VERSION 5.7 ;
BUSBITCHARS "[]" ;
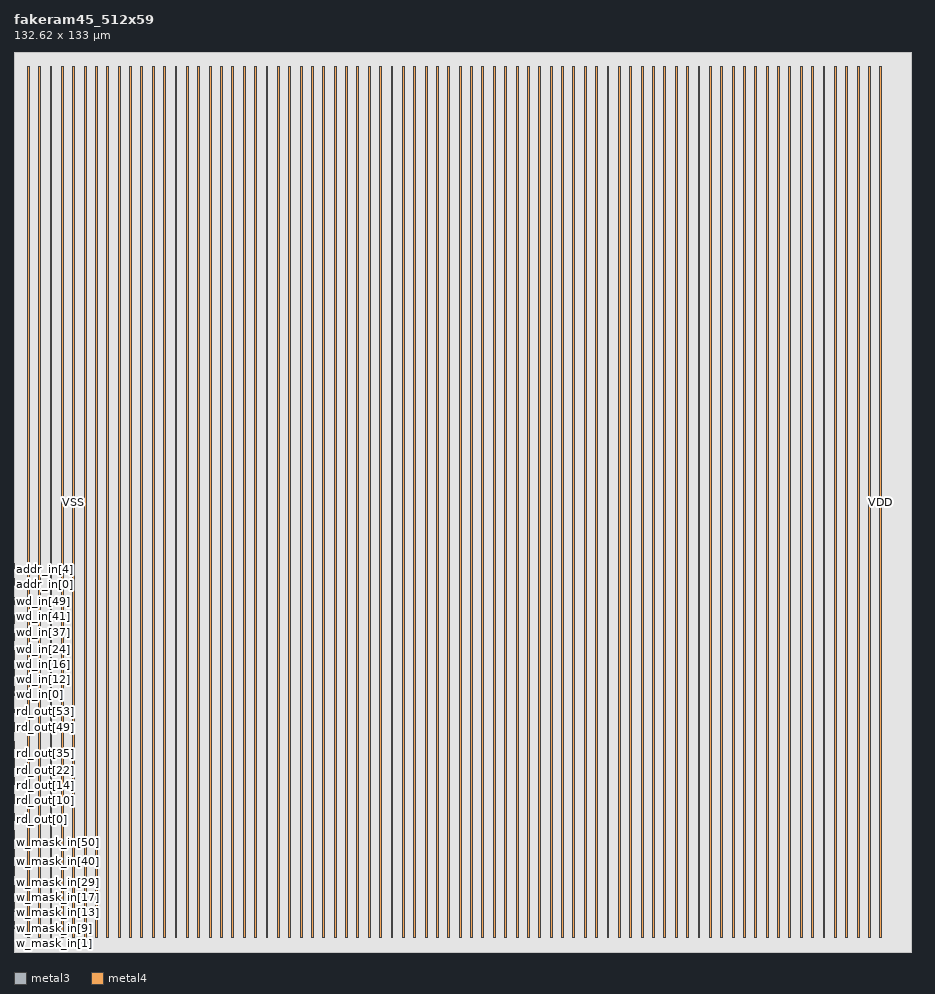
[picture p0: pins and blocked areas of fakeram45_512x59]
MACRO fakeram45_512x59
  FOREIGN fakeram45_512x59 0 0 ;
  SYMMETRY X Y R90 ;
  SIZE 132.620 BY 133.000 ;
  CLASS BLOCK ;
  PIN w_mask_in[0]
    DIRECTION INPUT ;
    USE SIGNAL ;
    SHAPE ABUTMENT ;
    PORT
      LAYER metal3 ;
      RECT 0.000 2.135 0.070 2.205 ;
    END
  END w_mask_in[0]
  PIN w_mask_in[1]
    DIRECTION INPUT ;
    USE SIGNAL ;
    SHAPE ABUTMENT ;
    PORT
      LAYER metal3 ;
      RECT 0.000 2.415 0.070 2.485 ;
    END
  END w_mask_in[1]
  PIN w_mask_in[2]
    DIRECTION INPUT ;
    USE SIGNAL ;
    SHAPE ABUTMENT ;
    PORT
      LAYER metal3 ;
      RECT 0.000 2.695 0.070 2.765 ;
    END
  END w_mask_in[2]
  PIN w_mask_in[3]
    DIRECTION INPUT ;
    USE SIGNAL ;
    SHAPE ABUTMENT ;
    PORT
      LAYER metal3 ;
      RECT 0.000 2.975 0.070 3.045 ;
    END
  END w_mask_in[3]
  PIN w_mask_in[4]
    DIRECTION INPUT ;
    USE SIGNAL ;
    SHAPE ABUTMENT ;
    PORT
      LAYER metal3 ;
      RECT 0.000 3.255 0.070 3.325 ;
    END
  END w_mask_in[4]
  PIN w_mask_in[5]
    DIRECTION INPUT ;
    USE SIGNAL ;
    SHAPE ABUTMENT ;
    PORT
      LAYER metal3 ;
      RECT 0.000 3.535 0.070 3.605 ;
    END
  END w_mask_in[5]
  PIN w_mask_in[6]
    DIRECTION INPUT ;
    USE SIGNAL ;
    SHAPE ABUTMENT ;
    PORT
      LAYER metal3 ;
      RECT 0.000 3.815 0.070 3.885 ;
    END
  END w_mask_in[6]
  PIN w_mask_in[7]
    DIRECTION INPUT ;
    USE SIGNAL ;
    SHAPE ABUTMENT ;
    PORT
      LAYER metal3 ;
      RECT 0.000 4.095 0.070 4.165 ;
    END
  END w_mask_in[7]
  PIN w_mask_in[8]
    DIRECTION INPUT ;
    USE SIGNAL ;
    SHAPE ABUTMENT ;
    PORT
      LAYER metal3 ;
      RECT 0.000 4.375 0.070 4.445 ;
    END
  END w_mask_in[8]
  PIN w_mask_in[9]
    DIRECTION INPUT ;
    USE SIGNAL ;
    SHAPE ABUTMENT ;
    PORT
      LAYER metal3 ;
      RECT 0.000 4.655 0.070 4.725 ;
    END
  END w_mask_in[9]
  PIN w_mask_in[10]
    DIRECTION INPUT ;
    USE SIGNAL ;
    SHAPE ABUTMENT ;
    PORT
      LAYER metal3 ;
      RECT 0.000 4.935 0.070 5.005 ;
    END
  END w_mask_in[10]
  PIN w_mask_in[11]
    DIRECTION INPUT ;
    USE SIGNAL ;
    SHAPE ABUTMENT ;
    PORT
      LAYER metal3 ;
      RECT 0.000 5.215 0.070 5.285 ;
    END
  END w_mask_in[11]
  PIN w_mask_in[12]
    DIRECTION INPUT ;
    USE SIGNAL ;
    SHAPE ABUTMENT ;
    PORT
      LAYER metal3 ;
      RECT 0.000 5.495 0.070 5.565 ;
    END
  END w_mask_in[12]
  PIN w_mask_in[13]
    DIRECTION INPUT ;
    USE SIGNAL ;
    SHAPE ABUTMENT ;
    PORT
      LAYER metal3 ;
      RECT 0.000 5.775 0.070 5.845 ;
    END
  END w_mask_in[13]
  PIN w_mask_in[14]
    DIRECTION INPUT ;
    USE SIGNAL ;
    SHAPE ABUTMENT ;
    PORT
      LAYER metal3 ;
      RECT 0.000 6.055 0.070 6.125 ;
    END
  END w_mask_in[14]
  PIN w_mask_in[15]
    DIRECTION INPUT ;
    USE SIGNAL ;
    SHAPE ABUTMENT ;
    PORT
      LAYER metal3 ;
      RECT 0.000 6.335 0.070 6.405 ;
    END
  END w_mask_in[15]
  PIN w_mask_in[16]
    DIRECTION INPUT ;
    USE SIGNAL ;
    SHAPE ABUTMENT ;
    PORT
      LAYER metal3 ;
      RECT 0.000 6.615 0.070 6.685 ;
    END
  END w_mask_in[16]
  PIN w_mask_in[17]
    DIRECTION INPUT ;
    USE SIGNAL ;
    SHAPE ABUTMENT ;
    PORT
      LAYER metal3 ;
      RECT 0.000 6.895 0.070 6.965 ;
    END
  END w_mask_in[17]
  PIN w_mask_in[18]
    DIRECTION INPUT ;
    USE SIGNAL ;
    SHAPE ABUTMENT ;
    PORT
      LAYER metal3 ;
      RECT 0.000 7.175 0.070 7.245 ;
    END
  END w_mask_in[18]
  PIN w_mask_in[19]
    DIRECTION INPUT ;
    USE SIGNAL ;
    SHAPE ABUTMENT ;
    PORT
      LAYER metal3 ;
      RECT 0.000 7.455 0.070 7.525 ;
    END
  END w_mask_in[19]
  PIN w_mask_in[20]
    DIRECTION INPUT ;
    USE SIGNAL ;
    SHAPE ABUTMENT ;
    PORT
      LAYER metal3 ;
      RECT 0.000 7.735 0.070 7.805 ;
    END
  END w_mask_in[20]
  PIN w_mask_in[21]
    DIRECTION INPUT ;
    USE SIGNAL ;
    SHAPE ABUTMENT ;
    PORT
      LAYER metal3 ;
      RECT 0.000 8.015 0.070 8.085 ;
    END
  END w_mask_in[21]
  PIN w_mask_in[22]
    DIRECTION INPUT ;
    USE SIGNAL ;
    SHAPE ABUTMENT ;
    PORT
      LAYER metal3 ;
      RECT 0.000 8.295 0.070 8.365 ;
    END
  END w_mask_in[22]
  PIN w_mask_in[23]
    DIRECTION INPUT ;
    USE SIGNAL ;
    SHAPE ABUTMENT ;
    PORT
      LAYER metal3 ;
      RECT 0.000 8.575 0.070 8.645 ;
    END
  END w_mask_in[23]
  PIN w_mask_in[24]
    DIRECTION INPUT ;
    USE SIGNAL ;
    SHAPE ABUTMENT ;
    PORT
      LAYER metal3 ;
      RECT 0.000 8.855 0.070 8.925 ;
    END
  END w_mask_in[24]
  PIN w_mask_in[25]
    DIRECTION INPUT ;
    USE SIGNAL ;
    SHAPE ABUTMENT ;
    PORT
      LAYER metal3 ;
      RECT 0.000 9.135 0.070 9.205 ;
    END
  END w_mask_in[25]
  PIN w_mask_in[26]
    DIRECTION INPUT ;
    USE SIGNAL ;
    SHAPE ABUTMENT ;
    PORT
      LAYER metal3 ;
      RECT 0.000 9.415 0.070 9.485 ;
    END
  END w_mask_in[26]
  PIN w_mask_in[27]
    DIRECTION INPUT ;
    USE SIGNAL ;
    SHAPE ABUTMENT ;
    PORT
      LAYER metal3 ;
      RECT 0.000 9.695 0.070 9.765 ;
    END
  END w_mask_in[27]
  PIN w_mask_in[28]
    DIRECTION INPUT ;
    USE SIGNAL ;
    SHAPE ABUTMENT ;
    PORT
      LAYER metal3 ;
      RECT 0.000 9.975 0.070 10.045 ;
    END
  END w_mask_in[28]
  PIN w_mask_in[29]
    DIRECTION INPUT ;
    USE SIGNAL ;
    SHAPE ABUTMENT ;
    PORT
      LAYER metal3 ;
      RECT 0.000 10.255 0.070 10.325 ;
    END
  END w_mask_in[29]
  PIN w_mask_in[30]
    DIRECTION INPUT ;
    USE SIGNAL ;
    SHAPE ABUTMENT ;
    PORT
      LAYER metal3 ;
      RECT 0.000 10.535 0.070 10.605 ;
    END
  END w_mask_in[30]
  PIN w_mask_in[31]
    DIRECTION INPUT ;
    USE SIGNAL ;
    SHAPE ABUTMENT ;
    PORT
      LAYER metal3 ;
      RECT 0.000 10.815 0.070 10.885 ;
    END
  END w_mask_in[31]
  PIN w_mask_in[32]
    DIRECTION INPUT ;
    USE SIGNAL ;
    SHAPE ABUTMENT ;
    PORT
      LAYER metal3 ;
      RECT 0.000 11.095 0.070 11.165 ;
    END
  END w_mask_in[32]
  PIN w_mask_in[33]
    DIRECTION INPUT ;
    USE SIGNAL ;
    SHAPE ABUTMENT ;
    PORT
      LAYER metal3 ;
      RECT 0.000 11.375 0.070 11.445 ;
    END
  END w_mask_in[33]
  PIN w_mask_in[34]
    DIRECTION INPUT ;
    USE SIGNAL ;
    SHAPE ABUTMENT ;
    PORT
      LAYER metal3 ;
      RECT 0.000 11.655 0.070 11.725 ;
    END
  END w_mask_in[34]
  PIN w_mask_in[35]
    DIRECTION INPUT ;
    USE SIGNAL ;
    SHAPE ABUTMENT ;
    PORT
      LAYER metal3 ;
      RECT 0.000 11.935 0.070 12.005 ;
    END
  END w_mask_in[35]
  PIN w_mask_in[36]
    DIRECTION INPUT ;
    USE SIGNAL ;
    SHAPE ABUTMENT ;
    PORT
      LAYER metal3 ;
      RECT 0.000 12.215 0.070 12.285 ;
    END
  END w_mask_in[36]
  PIN w_mask_in[37]
    DIRECTION INPUT ;
    USE SIGNAL ;
    SHAPE ABUTMENT ;
    PORT
      LAYER metal3 ;
      RECT 0.000 12.495 0.070 12.565 ;
    END
  END w_mask_in[37]
  PIN w_mask_in[38]
    DIRECTION INPUT ;
    USE SIGNAL ;
    SHAPE ABUTMENT ;
    PORT
      LAYER metal3 ;
      RECT 0.000 12.775 0.070 12.845 ;
    END
  END w_mask_in[38]
  PIN w_mask_in[39]
    DIRECTION INPUT ;
    USE SIGNAL ;
    SHAPE ABUTMENT ;
    PORT
      LAYER metal3 ;
      RECT 0.000 13.055 0.070 13.125 ;
    END
  END w_mask_in[39]
  PIN w_mask_in[40]
    DIRECTION INPUT ;
    USE SIGNAL ;
    SHAPE ABUTMENT ;
    PORT
      LAYER metal3 ;
      RECT 0.000 13.335 0.070 13.405 ;
    END
  END w_mask_in[40]
  PIN w_mask_in[41]
    DIRECTION INPUT ;
    USE SIGNAL ;
    SHAPE ABUTMENT ;
    PORT
      LAYER metal3 ;
      RECT 0.000 13.615 0.070 13.685 ;
    END
  END w_mask_in[41]
  PIN w_mask_in[42]
    DIRECTION INPUT ;
    USE SIGNAL ;
    SHAPE ABUTMENT ;
    PORT
      LAYER metal3 ;
      RECT 0.000 13.895 0.070 13.965 ;
    END
  END w_mask_in[42]
  PIN w_mask_in[43]
    DIRECTION INPUT ;
    USE SIGNAL ;
    SHAPE ABUTMENT ;
    PORT
      LAYER metal3 ;
      RECT 0.000 14.175 0.070 14.245 ;
    END
  END w_mask_in[43]
  PIN w_mask_in[44]
    DIRECTION INPUT ;
    USE SIGNAL ;
    SHAPE ABUTMENT ;
    PORT
      LAYER metal3 ;
      RECT 0.000 14.455 0.070 14.525 ;
    END
  END w_mask_in[44]
  PIN w_mask_in[45]
    DIRECTION INPUT ;
    USE SIGNAL ;
    SHAPE ABUTMENT ;
    PORT
      LAYER metal3 ;
      RECT 0.000 14.735 0.070 14.805 ;
    END
  END w_mask_in[45]
  PIN w_mask_in[46]
    DIRECTION INPUT ;
    USE SIGNAL ;
    SHAPE ABUTMENT ;
    PORT
      LAYER metal3 ;
      RECT 0.000 15.015 0.070 15.085 ;
    END
  END w_mask_in[46]
  PIN w_mask_in[47]
    DIRECTION INPUT ;
    USE SIGNAL ;
    SHAPE ABUTMENT ;
    PORT
      LAYER metal3 ;
      RECT 0.000 15.295 0.070 15.365 ;
    END
  END w_mask_in[47]
  PIN w_mask_in[48]
    DIRECTION INPUT ;
    USE SIGNAL ;
    SHAPE ABUTMENT ;
    PORT
      LAYER metal3 ;
      RECT 0.000 15.575 0.070 15.645 ;
    END
  END w_mask_in[48]
  PIN w_mask_in[49]
    DIRECTION INPUT ;
    USE SIGNAL ;
    SHAPE ABUTMENT ;
    PORT
      LAYER metal3 ;
      RECT 0.000 15.855 0.070 15.925 ;
    END
  END w_mask_in[49]
  PIN w_mask_in[50]
    DIRECTION INPUT ;
    USE SIGNAL ;
    SHAPE ABUTMENT ;
    PORT
      LAYER metal3 ;
      RECT 0.000 16.135 0.070 16.205 ;
    END
  END w_mask_in[50]
  PIN w_mask_in[51]
    DIRECTION INPUT ;
    USE SIGNAL ;
    SHAPE ABUTMENT ;
    PORT
      LAYER metal3 ;
      RECT 0.000 16.415 0.070 16.485 ;
    END
  END w_mask_in[51]
  PIN w_mask_in[52]
    DIRECTION INPUT ;
    USE SIGNAL ;
    SHAPE ABUTMENT ;
    PORT
      LAYER metal3 ;
      RECT 0.000 16.695 0.070 16.765 ;
    END
  END w_mask_in[52]
  PIN w_mask_in[53]
    DIRECTION INPUT ;
    USE SIGNAL ;
    SHAPE ABUTMENT ;
    PORT
      LAYER metal3 ;
      RECT 0.000 16.975 0.070 17.045 ;
    END
  END w_mask_in[53]
  PIN w_mask_in[54]
    DIRECTION INPUT ;
    USE SIGNAL ;
    SHAPE ABUTMENT ;
    PORT
      LAYER metal3 ;
      RECT 0.000 17.255 0.070 17.325 ;
    END
  END w_mask_in[54]
  PIN w_mask_in[55]
    DIRECTION INPUT ;
    USE SIGNAL ;
    SHAPE ABUTMENT ;
    PORT
      LAYER metal3 ;
      RECT 0.000 17.535 0.070 17.605 ;
    END
  END w_mask_in[55]
  PIN w_mask_in[56]
    DIRECTION INPUT ;
    USE SIGNAL ;
    SHAPE ABUTMENT ;
    PORT
      LAYER metal3 ;
      RECT 0.000 17.815 0.070 17.885 ;
    END
  END w_mask_in[56]
  PIN w_mask_in[57]
    DIRECTION INPUT ;
    USE SIGNAL ;
    SHAPE ABUTMENT ;
    PORT
      LAYER metal3 ;
      RECT 0.000 18.095 0.070 18.165 ;
    END
  END w_mask_in[57]
  PIN w_mask_in[58]
    DIRECTION INPUT ;
    USE SIGNAL ;
    SHAPE ABUTMENT ;
    PORT
      LAYER metal3 ;
      RECT 0.000 18.375 0.070 18.445 ;
    END
  END w_mask_in[58]
  PIN rd_out[0]
    DIRECTION OUTPUT ;
    USE SIGNAL ;
    SHAPE ABUTMENT ;
    PORT
      LAYER metal3 ;
      RECT 0.000 19.495 0.070 19.565 ;
    END
  END rd_out[0]
  PIN rd_out[1]
    DIRECTION OUTPUT ;
    USE SIGNAL ;
    SHAPE ABUTMENT ;
    PORT
      LAYER metal3 ;
      RECT 0.000 19.775 0.070 19.845 ;
    END
  END rd_out[1]
  PIN rd_out[2]
    DIRECTION OUTPUT ;
    USE SIGNAL ;
    SHAPE ABUTMENT ;
    PORT
      LAYER metal3 ;
      RECT 0.000 20.055 0.070 20.125 ;
    END
  END rd_out[2]
  PIN rd_out[3]
    DIRECTION OUTPUT ;
    USE SIGNAL ;
    SHAPE ABUTMENT ;
    PORT
      LAYER metal3 ;
      RECT 0.000 20.335 0.070 20.405 ;
    END
  END rd_out[3]
  PIN rd_out[4]
    DIRECTION OUTPUT ;
    USE SIGNAL ;
    SHAPE ABUTMENT ;
    PORT
      LAYER metal3 ;
      RECT 0.000 20.615 0.070 20.685 ;
    END
  END rd_out[4]
  PIN rd_out[5]
    DIRECTION OUTPUT ;
    USE SIGNAL ;
    SHAPE ABUTMENT ;
    PORT
      LAYER metal3 ;
      RECT 0.000 20.895 0.070 20.965 ;
    END
  END rd_out[5]
  PIN rd_out[6]
    DIRECTION OUTPUT ;
    USE SIGNAL ;
    SHAPE ABUTMENT ;
    PORT
      LAYER metal3 ;
      RECT 0.000 21.175 0.070 21.245 ;
    END
  END rd_out[6]
  PIN rd_out[7]
    DIRECTION OUTPUT ;
    USE SIGNAL ;
    SHAPE ABUTMENT ;
    PORT
      LAYER metal3 ;
      RECT 0.000 21.455 0.070 21.525 ;
    END
  END rd_out[7]
  PIN rd_out[8]
    DIRECTION OUTPUT ;
    USE SIGNAL ;
    SHAPE ABUTMENT ;
    PORT
      LAYER metal3 ;
      RECT 0.000 21.735 0.070 21.805 ;
    END
  END rd_out[8]
  PIN rd_out[9]
    DIRECTION OUTPUT ;
    USE SIGNAL ;
    SHAPE ABUTMENT ;
    PORT
      LAYER metal3 ;
      RECT 0.000 22.015 0.070 22.085 ;
    END
  END rd_out[9]
  PIN rd_out[10]
    DIRECTION OUTPUT ;
    USE SIGNAL ;
    SHAPE ABUTMENT ;
    PORT
      LAYER metal3 ;
      RECT 0.000 22.295 0.070 22.365 ;
    END
  END rd_out[10]
  PIN rd_out[11]
    DIRECTION OUTPUT ;
    USE SIGNAL ;
    SHAPE ABUTMENT ;
    PORT
      LAYER metal3 ;
      RECT 0.000 22.575 0.070 22.645 ;
    END
  END rd_out[11]
  PIN rd_out[12]
    DIRECTION OUTPUT ;
    USE SIGNAL ;
    SHAPE ABUTMENT ;
    PORT
      LAYER metal3 ;
      RECT 0.000 22.855 0.070 22.925 ;
    END
  END rd_out[12]
  PIN rd_out[13]
    DIRECTION OUTPUT ;
    USE SIGNAL ;
    SHAPE ABUTMENT ;
    PORT
      LAYER metal3 ;
      RECT 0.000 23.135 0.070 23.205 ;
    END
  END rd_out[13]
  PIN rd_out[14]
    DIRECTION OUTPUT ;
    USE SIGNAL ;
    SHAPE ABUTMENT ;
    PORT
      LAYER metal3 ;
      RECT 0.000 23.415 0.070 23.485 ;
    END
  END rd_out[14]
  PIN rd_out[15]
    DIRECTION OUTPUT ;
    USE SIGNAL ;
    SHAPE ABUTMENT ;
    PORT
      LAYER metal3 ;
      RECT 0.000 23.695 0.070 23.765 ;
    END
  END rd_out[15]
  PIN rd_out[16]
    DIRECTION OUTPUT ;
    USE SIGNAL ;
    SHAPE ABUTMENT ;
    PORT
      LAYER metal3 ;
      RECT 0.000 23.975 0.070 24.045 ;
    END
  END rd_out[16]
  PIN rd_out[17]
    DIRECTION OUTPUT ;
    USE SIGNAL ;
    SHAPE ABUTMENT ;
    PORT
      LAYER metal3 ;
      RECT 0.000 24.255 0.070 24.325 ;
    END
  END rd_out[17]
  PIN rd_out[18]
    DIRECTION OUTPUT ;
    USE SIGNAL ;
    SHAPE ABUTMENT ;
    PORT
      LAYER metal3 ;
      RECT 0.000 24.535 0.070 24.605 ;
    END
  END rd_out[18]
  PIN rd_out[19]
    DIRECTION OUTPUT ;
    USE SIGNAL ;
    SHAPE ABUTMENT ;
    PORT
      LAYER metal3 ;
      RECT 0.000 24.815 0.070 24.885 ;
    END
  END rd_out[19]
  PIN rd_out[20]
    DIRECTION OUTPUT ;
    USE SIGNAL ;
    SHAPE ABUTMENT ;
    PORT
      LAYER metal3 ;
      RECT 0.000 25.095 0.070 25.165 ;
    END
  END rd_out[20]
  PIN rd_out[21]
    DIRECTION OUTPUT ;
    USE SIGNAL ;
    SHAPE ABUTMENT ;
    PORT
      LAYER metal3 ;
      RECT 0.000 25.375 0.070 25.445 ;
    END
  END rd_out[21]
  PIN rd_out[22]
    DIRECTION OUTPUT ;
    USE SIGNAL ;
    SHAPE ABUTMENT ;
    PORT
      LAYER metal3 ;
      RECT 0.000 25.655 0.070 25.725 ;
    END
  END rd_out[22]
  PIN rd_out[23]
    DIRECTION OUTPUT ;
    USE SIGNAL ;
    SHAPE ABUTMENT ;
    PORT
      LAYER metal3 ;
      RECT 0.000 25.935 0.070 26.005 ;
    END
  END rd_out[23]
  PIN rd_out[24]
    DIRECTION OUTPUT ;
    USE SIGNAL ;
    SHAPE ABUTMENT ;
    PORT
      LAYER metal3 ;
      RECT 0.000 26.215 0.070 26.285 ;
    END
  END rd_out[24]
  PIN rd_out[25]
    DIRECTION OUTPUT ;
    USE SIGNAL ;
    SHAPE ABUTMENT ;
    PORT
      LAYER metal3 ;
      RECT 0.000 26.495 0.070 26.565 ;
    END
  END rd_out[25]
  PIN rd_out[26]
    DIRECTION OUTPUT ;
    USE SIGNAL ;
    SHAPE ABUTMENT ;
    PORT
      LAYER metal3 ;
      RECT 0.000 26.775 0.070 26.845 ;
    END
  END rd_out[26]
  PIN rd_out[27]
    DIRECTION OUTPUT ;
    USE SIGNAL ;
    SHAPE ABUTMENT ;
    PORT
      LAYER metal3 ;
      RECT 0.000 27.055 0.070 27.125 ;
    END
  END rd_out[27]
  PIN rd_out[28]
    DIRECTION OUTPUT ;
    USE SIGNAL ;
    SHAPE ABUTMENT ;
    PORT
      LAYER metal3 ;
      RECT 0.000 27.335 0.070 27.405 ;
    END
  END rd_out[28]
  PIN rd_out[29]
    DIRECTION OUTPUT ;
    USE SIGNAL ;
    SHAPE ABUTMENT ;
    PORT
      LAYER metal3 ;
      RECT 0.000 27.615 0.070 27.685 ;
    END
  END rd_out[29]
  PIN rd_out[30]
    DIRECTION OUTPUT ;
    USE SIGNAL ;
    SHAPE ABUTMENT ;
    PORT
      LAYER metal3 ;
      RECT 0.000 27.895 0.070 27.965 ;
    END
  END rd_out[30]
  PIN rd_out[31]
    DIRECTION OUTPUT ;
    USE SIGNAL ;
    SHAPE ABUTMENT ;
    PORT
      LAYER metal3 ;
      RECT 0.000 28.175 0.070 28.245 ;
    END
  END rd_out[31]
  PIN rd_out[32]
    DIRECTION OUTPUT ;
    USE SIGNAL ;
    SHAPE ABUTMENT ;
    PORT
      LAYER metal3 ;
      RECT 0.000 28.455 0.070 28.525 ;
    END
  END rd_out[32]
  PIN rd_out[33]
    DIRECTION OUTPUT ;
    USE SIGNAL ;
    SHAPE ABUTMENT ;
    PORT
      LAYER metal3 ;
      RECT 0.000 28.735 0.070 28.805 ;
    END
  END rd_out[33]
  PIN rd_out[34]
    DIRECTION OUTPUT ;
    USE SIGNAL ;
    SHAPE ABUTMENT ;
    PORT
      LAYER metal3 ;
      RECT 0.000 29.015 0.070 29.085 ;
    END
  END rd_out[34]
  PIN rd_out[35]
    DIRECTION OUTPUT ;
    USE SIGNAL ;
    SHAPE ABUTMENT ;
    PORT
      LAYER metal3 ;
      RECT 0.000 29.295 0.070 29.365 ;
    END
  END rd_out[35]
  PIN rd_out[36]
    DIRECTION OUTPUT ;
    USE SIGNAL ;
    SHAPE ABUTMENT ;
    PORT
      LAYER metal3 ;
      RECT 0.000 29.575 0.070 29.645 ;
    END
  END rd_out[36]
  PIN rd_out[37]
    DIRECTION OUTPUT ;
    USE SIGNAL ;
    SHAPE ABUTMENT ;
    PORT
      LAYER metal3 ;
      RECT 0.000 29.855 0.070 29.925 ;
    END
  END rd_out[37]
  PIN rd_out[38]
    DIRECTION OUTPUT ;
    USE SIGNAL ;
    SHAPE ABUTMENT ;
    PORT
      LAYER metal3 ;
      RECT 0.000 30.135 0.070 30.205 ;
    END
  END rd_out[38]
  PIN rd_out[39]
    DIRECTION OUTPUT ;
    USE SIGNAL ;
    SHAPE ABUTMENT ;
    PORT
      LAYER metal3 ;
      RECT 0.000 30.415 0.070 30.485 ;
    END
  END rd_out[39]
  PIN rd_out[40]
    DIRECTION OUTPUT ;
    USE SIGNAL ;
    SHAPE ABUTMENT ;
    PORT
      LAYER metal3 ;
      RECT 0.000 30.695 0.070 30.765 ;
    END
  END rd_out[40]
  PIN rd_out[41]
    DIRECTION OUTPUT ;
    USE SIGNAL ;
    SHAPE ABUTMENT ;
    PORT
      LAYER metal3 ;
      RECT 0.000 30.975 0.070 31.045 ;
    END
  END rd_out[41]
  PIN rd_out[42]
    DIRECTION OUTPUT ;
    USE SIGNAL ;
    SHAPE ABUTMENT ;
    PORT
      LAYER metal3 ;
      RECT 0.000 31.255 0.070 31.325 ;
    END
  END rd_out[42]
  PIN rd_out[43]
    DIRECTION OUTPUT ;
    USE SIGNAL ;
    SHAPE ABUTMENT ;
    PORT
      LAYER metal3 ;
      RECT 0.000 31.535 0.070 31.605 ;
    END
  END rd_out[43]
  PIN rd_out[44]
    DIRECTION OUTPUT ;
    USE SIGNAL ;
    SHAPE ABUTMENT ;
    PORT
      LAYER metal3 ;
      RECT 0.000 31.815 0.070 31.885 ;
    END
  END rd_out[44]
  PIN rd_out[45]
    DIRECTION OUTPUT ;
    USE SIGNAL ;
    SHAPE ABUTMENT ;
    PORT
      LAYER metal3 ;
      RECT 0.000 32.095 0.070 32.165 ;
    END
  END rd_out[45]
  PIN rd_out[46]
    DIRECTION OUTPUT ;
    USE SIGNAL ;
    SHAPE ABUTMENT ;
    PORT
      LAYER metal3 ;
      RECT 0.000 32.375 0.070 32.445 ;
    END
  END rd_out[46]
  PIN rd_out[47]
    DIRECTION OUTPUT ;
    USE SIGNAL ;
    SHAPE ABUTMENT ;
    PORT
      LAYER metal3 ;
      RECT 0.000 32.655 0.070 32.725 ;
    END
  END rd_out[47]
  PIN rd_out[48]
    DIRECTION OUTPUT ;
    USE SIGNAL ;
    SHAPE ABUTMENT ;
    PORT
      LAYER metal3 ;
      RECT 0.000 32.935 0.070 33.005 ;
    END
  END rd_out[48]
  PIN rd_out[49]
    DIRECTION OUTPUT ;
    USE SIGNAL ;
    SHAPE ABUTMENT ;
    PORT
      LAYER metal3 ;
      RECT 0.000 33.215 0.070 33.285 ;
    END
  END rd_out[49]
  PIN rd_out[50]
    DIRECTION OUTPUT ;
    USE SIGNAL ;
    SHAPE ABUTMENT ;
    PORT
      LAYER metal3 ;
      RECT 0.000 33.495 0.070 33.565 ;
    END
  END rd_out[50]
  PIN rd_out[51]
    DIRECTION OUTPUT ;
    USE SIGNAL ;
    SHAPE ABUTMENT ;
    PORT
      LAYER metal3 ;
      RECT 0.000 33.775 0.070 33.845 ;
    END
  END rd_out[51]
  PIN rd_out[52]
    DIRECTION OUTPUT ;
    USE SIGNAL ;
    SHAPE ABUTMENT ;
    PORT
      LAYER metal3 ;
      RECT 0.000 34.055 0.070 34.125 ;
    END
  END rd_out[52]
  PIN rd_out[53]
    DIRECTION OUTPUT ;
    USE SIGNAL ;
    SHAPE ABUTMENT ;
    PORT
      LAYER metal3 ;
      RECT 0.000 34.335 0.070 34.405 ;
    END
  END rd_out[53]
  PIN rd_out[54]
    DIRECTION OUTPUT ;
    USE SIGNAL ;
    SHAPE ABUTMENT ;
    PORT
      LAYER metal3 ;
      RECT 0.000 34.615 0.070 34.685 ;
    END
  END rd_out[54]
  PIN rd_out[55]
    DIRECTION OUTPUT ;
    USE SIGNAL ;
    SHAPE ABUTMENT ;
    PORT
      LAYER metal3 ;
      RECT 0.000 34.895 0.070 34.965 ;
    END
  END rd_out[55]
  PIN rd_out[56]
    DIRECTION OUTPUT ;
    USE SIGNAL ;
    SHAPE ABUTMENT ;
    PORT
      LAYER metal3 ;
      RECT 0.000 35.175 0.070 35.245 ;
    END
  END rd_out[56]
  PIN rd_out[57]
    DIRECTION OUTPUT ;
    USE SIGNAL ;
    SHAPE ABUTMENT ;
    PORT
      LAYER metal3 ;
      RECT 0.000 35.455 0.070 35.525 ;
    END
  END rd_out[57]
  PIN rd_out[58]
    DIRECTION OUTPUT ;
    USE SIGNAL ;
    SHAPE ABUTMENT ;
    PORT
      LAYER metal3 ;
      RECT 0.000 35.735 0.070 35.805 ;
    END
  END rd_out[58]
  PIN wd_in[0]
    DIRECTION INPUT ;
    USE SIGNAL ;
    SHAPE ABUTMENT ;
    PORT
      LAYER metal3 ;
      RECT 0.000 36.855 0.070 36.925 ;
    END
  END wd_in[0]
  PIN wd_in[1]
    DIRECTION INPUT ;
    USE SIGNAL ;
    SHAPE ABUTMENT ;
    PORT
      LAYER metal3 ;
      RECT 0.000 37.135 0.070 37.205 ;
    END
  END wd_in[1]
  PIN wd_in[2]
    DIRECTION INPUT ;
    USE SIGNAL ;
    SHAPE ABUTMENT ;
    PORT
      LAYER metal3 ;
      RECT 0.000 37.415 0.070 37.485 ;
    END
  END wd_in[2]
  PIN wd_in[3]
    DIRECTION INPUT ;
    USE SIGNAL ;
    SHAPE ABUTMENT ;
    PORT
      LAYER metal3 ;
      RECT 0.000 37.695 0.070 37.765 ;
    END
  END wd_in[3]
  PIN wd_in[4]
    DIRECTION INPUT ;
    USE SIGNAL ;
    SHAPE ABUTMENT ;
    PORT
      LAYER metal3 ;
      RECT 0.000 37.975 0.070 38.045 ;
    END
  END wd_in[4]
  PIN wd_in[5]
    DIRECTION INPUT ;
    USE SIGNAL ;
    SHAPE ABUTMENT ;
    PORT
      LAYER metal3 ;
      RECT 0.000 38.255 0.070 38.325 ;
    END
  END wd_in[5]
  PIN wd_in[6]
    DIRECTION INPUT ;
    USE SIGNAL ;
    SHAPE ABUTMENT ;
    PORT
      LAYER metal3 ;
      RECT 0.000 38.535 0.070 38.605 ;
    END
  END wd_in[6]
  PIN wd_in[7]
    DIRECTION INPUT ;
    USE SIGNAL ;
    SHAPE ABUTMENT ;
    PORT
      LAYER metal3 ;
      RECT 0.000 38.815 0.070 38.885 ;
    END
  END wd_in[7]
  PIN wd_in[8]
    DIRECTION INPUT ;
    USE SIGNAL ;
    SHAPE ABUTMENT ;
    PORT
      LAYER metal3 ;
      RECT 0.000 39.095 0.070 39.165 ;
    END
  END wd_in[8]
  PIN wd_in[9]
    DIRECTION INPUT ;
    USE SIGNAL ;
    SHAPE ABUTMENT ;
    PORT
      LAYER metal3 ;
      RECT 0.000 39.375 0.070 39.445 ;
    END
  END wd_in[9]
  PIN wd_in[10]
    DIRECTION INPUT ;
    USE SIGNAL ;
    SHAPE ABUTMENT ;
    PORT
      LAYER metal3 ;
      RECT 0.000 39.655 0.070 39.725 ;
    END
  END wd_in[10]
  PIN wd_in[11]
    DIRECTION INPUT ;
    USE SIGNAL ;
    SHAPE ABUTMENT ;
    PORT
      LAYER metal3 ;
      RECT 0.000 39.935 0.070 40.005 ;
    END
  END wd_in[11]
  PIN wd_in[12]
    DIRECTION INPUT ;
    USE SIGNAL ;
    SHAPE ABUTMENT ;
    PORT
      LAYER metal3 ;
      RECT 0.000 40.215 0.070 40.285 ;
    END
  END wd_in[12]
  PIN wd_in[13]
    DIRECTION INPUT ;
    USE SIGNAL ;
    SHAPE ABUTMENT ;
    PORT
      LAYER metal3 ;
      RECT 0.000 40.495 0.070 40.565 ;
    END
  END wd_in[13]
  PIN wd_in[14]
    DIRECTION INPUT ;
    USE SIGNAL ;
    SHAPE ABUTMENT ;
    PORT
      LAYER metal3 ;
      RECT 0.000 40.775 0.070 40.845 ;
    END
  END wd_in[14]
  PIN wd_in[15]
    DIRECTION INPUT ;
    USE SIGNAL ;
    SHAPE ABUTMENT ;
    PORT
      LAYER metal3 ;
      RECT 0.000 41.055 0.070 41.125 ;
    END
  END wd_in[15]
  PIN wd_in[16]
    DIRECTION INPUT ;
    USE SIGNAL ;
    SHAPE ABUTMENT ;
    PORT
      LAYER metal3 ;
      RECT 0.000 41.335 0.070 41.405 ;
    END
  END wd_in[16]
  PIN wd_in[17]
    DIRECTION INPUT ;
    USE SIGNAL ;
    SHAPE ABUTMENT ;
    PORT
      LAYER metal3 ;
      RECT 0.000 41.615 0.070 41.685 ;
    END
  END wd_in[17]
  PIN wd_in[18]
    DIRECTION INPUT ;
    USE SIGNAL ;
    SHAPE ABUTMENT ;
    PORT
      LAYER metal3 ;
      RECT 0.000 41.895 0.070 41.965 ;
    END
  END wd_in[18]
  PIN wd_in[19]
    DIRECTION INPUT ;
    USE SIGNAL ;
    SHAPE ABUTMENT ;
    PORT
      LAYER metal3 ;
      RECT 0.000 42.175 0.070 42.245 ;
    END
  END wd_in[19]
  PIN wd_in[20]
    DIRECTION INPUT ;
    USE SIGNAL ;
    SHAPE ABUTMENT ;
    PORT
      LAYER metal3 ;
      RECT 0.000 42.455 0.070 42.525 ;
    END
  END wd_in[20]
  PIN wd_in[21]
    DIRECTION INPUT ;
    USE SIGNAL ;
    SHAPE ABUTMENT ;
    PORT
      LAYER metal3 ;
      RECT 0.000 42.735 0.070 42.805 ;
    END
  END wd_in[21]
  PIN wd_in[22]
    DIRECTION INPUT ;
    USE SIGNAL ;
    SHAPE ABUTMENT ;
    PORT
      LAYER metal3 ;
      RECT 0.000 43.015 0.070 43.085 ;
    END
  END wd_in[22]
  PIN wd_in[23]
    DIRECTION INPUT ;
    USE SIGNAL ;
    SHAPE ABUTMENT ;
    PORT
      LAYER metal3 ;
      RECT 0.000 43.295 0.070 43.365 ;
    END
  END wd_in[23]
  PIN wd_in[24]
    DIRECTION INPUT ;
    USE SIGNAL ;
    SHAPE ABUTMENT ;
    PORT
      LAYER metal3 ;
      RECT 0.000 43.575 0.070 43.645 ;
    END
  END wd_in[24]
  PIN wd_in[25]
    DIRECTION INPUT ;
    USE SIGNAL ;
    SHAPE ABUTMENT ;
    PORT
      LAYER metal3 ;
      RECT 0.000 43.855 0.070 43.925 ;
    END
  END wd_in[25]
  PIN wd_in[26]
    DIRECTION INPUT ;
    USE SIGNAL ;
    SHAPE ABUTMENT ;
    PORT
      LAYER metal3 ;
      RECT 0.000 44.135 0.070 44.205 ;
    END
  END wd_in[26]
  PIN wd_in[27]
    DIRECTION INPUT ;
    USE SIGNAL ;
    SHAPE ABUTMENT ;
    PORT
      LAYER metal3 ;
      RECT 0.000 44.415 0.070 44.485 ;
    END
  END wd_in[27]
  PIN wd_in[28]
    DIRECTION INPUT ;
    USE SIGNAL ;
    SHAPE ABUTMENT ;
    PORT
      LAYER metal3 ;
      RECT 0.000 44.695 0.070 44.765 ;
    END
  END wd_in[28]
  PIN wd_in[29]
    DIRECTION INPUT ;
    USE SIGNAL ;
    SHAPE ABUTMENT ;
    PORT
      LAYER metal3 ;
      RECT 0.000 44.975 0.070 45.045 ;
    END
  END wd_in[29]
  PIN wd_in[30]
    DIRECTION INPUT ;
    USE SIGNAL ;
    SHAPE ABUTMENT ;
    PORT
      LAYER metal3 ;
      RECT 0.000 45.255 0.070 45.325 ;
    END
  END wd_in[30]
  PIN wd_in[31]
    DIRECTION INPUT ;
    USE SIGNAL ;
    SHAPE ABUTMENT ;
    PORT
      LAYER metal3 ;
      RECT 0.000 45.535 0.070 45.605 ;
    END
  END wd_in[31]
  PIN wd_in[32]
    DIRECTION INPUT ;
    USE SIGNAL ;
    SHAPE ABUTMENT ;
    PORT
      LAYER metal3 ;
      RECT 0.000 45.815 0.070 45.885 ;
    END
  END wd_in[32]
  PIN wd_in[33]
    DIRECTION INPUT ;
    USE SIGNAL ;
    SHAPE ABUTMENT ;
    PORT
      LAYER metal3 ;
      RECT 0.000 46.095 0.070 46.165 ;
    END
  END wd_in[33]
  PIN wd_in[34]
    DIRECTION INPUT ;
    USE SIGNAL ;
    SHAPE ABUTMENT ;
    PORT
      LAYER metal3 ;
      RECT 0.000 46.375 0.070 46.445 ;
    END
  END wd_in[34]
  PIN wd_in[35]
    DIRECTION INPUT ;
    USE SIGNAL ;
    SHAPE ABUTMENT ;
    PORT
      LAYER metal3 ;
      RECT 0.000 46.655 0.070 46.725 ;
    END
  END wd_in[35]
  PIN wd_in[36]
    DIRECTION INPUT ;
    USE SIGNAL ;
    SHAPE ABUTMENT ;
    PORT
      LAYER metal3 ;
      RECT 0.000 46.935 0.070 47.005 ;
    END
  END wd_in[36]
  PIN wd_in[37]
    DIRECTION INPUT ;
    USE SIGNAL ;
    SHAPE ABUTMENT ;
    PORT
      LAYER metal3 ;
      RECT 0.000 47.215 0.070 47.285 ;
    END
  END wd_in[37]
  PIN wd_in[38]
    DIRECTION INPUT ;
    USE SIGNAL ;
    SHAPE ABUTMENT ;
    PORT
      LAYER metal3 ;
      RECT 0.000 47.495 0.070 47.565 ;
    END
  END wd_in[38]
  PIN wd_in[39]
    DIRECTION INPUT ;
    USE SIGNAL ;
    SHAPE ABUTMENT ;
    PORT
      LAYER metal3 ;
      RECT 0.000 47.775 0.070 47.845 ;
    END
  END wd_in[39]
  PIN wd_in[40]
    DIRECTION INPUT ;
    USE SIGNAL ;
    SHAPE ABUTMENT ;
    PORT
      LAYER metal3 ;
      RECT 0.000 48.055 0.070 48.125 ;
    END
  END wd_in[40]
  PIN wd_in[41]
    DIRECTION INPUT ;
    USE SIGNAL ;
    SHAPE ABUTMENT ;
    PORT
      LAYER metal3 ;
      RECT 0.000 48.335 0.070 48.405 ;
    END
  END wd_in[41]
  PIN wd_in[42]
    DIRECTION INPUT ;
    USE SIGNAL ;
    SHAPE ABUTMENT ;
    PORT
      LAYER metal3 ;
      RECT 0.000 48.615 0.070 48.685 ;
    END
  END wd_in[42]
  PIN wd_in[43]
    DIRECTION INPUT ;
    USE SIGNAL ;
    SHAPE ABUTMENT ;
    PORT
      LAYER metal3 ;
      RECT 0.000 48.895 0.070 48.965 ;
    END
  END wd_in[43]
  PIN wd_in[44]
    DIRECTION INPUT ;
    USE SIGNAL ;
    SHAPE ABUTMENT ;
    PORT
      LAYER metal3 ;
      RECT 0.000 49.175 0.070 49.245 ;
    END
  END wd_in[44]
  PIN wd_in[45]
    DIRECTION INPUT ;
    USE SIGNAL ;
    SHAPE ABUTMENT ;
    PORT
      LAYER metal3 ;
      RECT 0.000 49.455 0.070 49.525 ;
    END
  END wd_in[45]
  PIN wd_in[46]
    DIRECTION INPUT ;
    USE SIGNAL ;
    SHAPE ABUTMENT ;
    PORT
      LAYER metal3 ;
      RECT 0.000 49.735 0.070 49.805 ;
    END
  END wd_in[46]
  PIN wd_in[47]
    DIRECTION INPUT ;
    USE SIGNAL ;
    SHAPE ABUTMENT ;
    PORT
      LAYER metal3 ;
      RECT 0.000 50.015 0.070 50.085 ;
    END
  END wd_in[47]
  PIN wd_in[48]
    DIRECTION INPUT ;
    USE SIGNAL ;
    SHAPE ABUTMENT ;
    PORT
      LAYER metal3 ;
      RECT 0.000 50.295 0.070 50.365 ;
    END
  END wd_in[48]
  PIN wd_in[49]
    DIRECTION INPUT ;
    USE SIGNAL ;
    SHAPE ABUTMENT ;
    PORT
      LAYER metal3 ;
      RECT 0.000 50.575 0.070 50.645 ;
    END
  END wd_in[49]
  PIN wd_in[50]
    DIRECTION INPUT ;
    USE SIGNAL ;
    SHAPE ABUTMENT ;
    PORT
      LAYER metal3 ;
      RECT 0.000 50.855 0.070 50.925 ;
    END
  END wd_in[50]
  PIN wd_in[51]
    DIRECTION INPUT ;
    USE SIGNAL ;
    SHAPE ABUTMENT ;
    PORT
      LAYER metal3 ;
      RECT 0.000 51.135 0.070 51.205 ;
    END
  END wd_in[51]
  PIN wd_in[52]
    DIRECTION INPUT ;
    USE SIGNAL ;
    SHAPE ABUTMENT ;
    PORT
      LAYER metal3 ;
      RECT 0.000 51.415 0.070 51.485 ;
    END
  END wd_in[52]
  PIN wd_in[53]
    DIRECTION INPUT ;
    USE SIGNAL ;
    SHAPE ABUTMENT ;
    PORT
      LAYER metal3 ;
      RECT 0.000 51.695 0.070 51.765 ;
    END
  END wd_in[53]
  PIN wd_in[54]
    DIRECTION INPUT ;
    USE SIGNAL ;
    SHAPE ABUTMENT ;
    PORT
      LAYER metal3 ;
      RECT 0.000 51.975 0.070 52.045 ;
    END
  END wd_in[54]
  PIN wd_in[55]
    DIRECTION INPUT ;
    USE SIGNAL ;
    SHAPE ABUTMENT ;
    PORT
      LAYER metal3 ;
      RECT 0.000 52.255 0.070 52.325 ;
    END
  END wd_in[55]
  PIN wd_in[56]
    DIRECTION INPUT ;
    USE SIGNAL ;
    SHAPE ABUTMENT ;
    PORT
      LAYER metal3 ;
      RECT 0.000 52.535 0.070 52.605 ;
    END
  END wd_in[56]
  PIN wd_in[57]
    DIRECTION INPUT ;
    USE SIGNAL ;
    SHAPE ABUTMENT ;
    PORT
      LAYER metal3 ;
      RECT 0.000 52.815 0.070 52.885 ;
    END
  END wd_in[57]
  PIN wd_in[58]
    DIRECTION INPUT ;
    USE SIGNAL ;
    SHAPE ABUTMENT ;
    PORT
      LAYER metal3 ;
      RECT 0.000 53.095 0.070 53.165 ;
    END
  END wd_in[58]
  PIN addr_in[0]
    DIRECTION INPUT ;
    USE SIGNAL ;
    SHAPE ABUTMENT ;
    PORT
      LAYER metal3 ;
      RECT 0.000 54.215 0.070 54.285 ;
    END
  END addr_in[0]
  PIN addr_in[1]
    DIRECTION INPUT ;
    USE SIGNAL ;
    SHAPE ABUTMENT ;
    PORT
      LAYER metal3 ;
      RECT 0.000 54.495 0.070 54.565 ;
    END
  END addr_in[1]
  PIN addr_in[2]
    DIRECTION INPUT ;
    USE SIGNAL ;
    SHAPE ABUTMENT ;
    PORT
      LAYER metal3 ;
      RECT 0.000 54.775 0.070 54.845 ;
    END
  END addr_in[2]
  PIN addr_in[3]
    DIRECTION INPUT ;
    USE SIGNAL ;
    SHAPE ABUTMENT ;
    PORT
      LAYER metal3 ;
      RECT 0.000 55.055 0.070 55.125 ;
    END
  END addr_in[3]
  PIN addr_in[4]
    DIRECTION INPUT ;
    USE SIGNAL ;
    SHAPE ABUTMENT ;
    PORT
      LAYER metal3 ;
      RECT 0.000 55.335 0.070 55.405 ;
    END
  END addr_in[4]
  PIN addr_in[5]
    DIRECTION INPUT ;
    USE SIGNAL ;
    SHAPE ABUTMENT ;
    PORT
      LAYER metal3 ;
      RECT 0.000 55.615 0.070 55.685 ;
    END
  END addr_in[5]
  PIN addr_in[6]
    DIRECTION INPUT ;
    USE SIGNAL ;
    SHAPE ABUTMENT ;
    PORT
      LAYER metal3 ;
      RECT 0.000 55.895 0.070 55.965 ;
    END
  END addr_in[6]
  PIN addr_in[7]
    DIRECTION INPUT ;
    USE SIGNAL ;
    SHAPE ABUTMENT ;
    PORT
      LAYER metal3 ;
      RECT 0.000 56.175 0.070 56.245 ;
    END
  END addr_in[7]
  PIN addr_in[8]
    DIRECTION INPUT ;
    USE SIGNAL ;
    SHAPE ABUTMENT ;
    PORT
      LAYER metal3 ;
      RECT 0.000 56.455 0.070 56.525 ;
    END
  END addr_in[8]
  PIN we_in
    DIRECTION INPUT ;
    USE SIGNAL ;
    SHAPE ABUTMENT ;
    PORT
      LAYER metal3 ;
      RECT 0.000 56.735 0.070 56.805 ;
    END
  END we_in
  PIN ce_in
    DIRECTION INPUT ;
    USE SIGNAL ;
    SHAPE ABUTMENT ;
    PORT
      LAYER metal3 ;
      RECT 0.000 57.015 0.070 57.085 ;
    END
  END ce_in
  PIN clk
    DIRECTION INPUT ;
    USE SIGNAL ;
    SHAPE ABUTMENT ;
    PORT
      LAYER metal3 ;
      RECT 0.000 57.295 0.070 57.365 ;
    END
  END clk
  PIN VSS
    DIRECTION INOUT ;
    USE GROUND ;
    PORT
      LAYER metal4 ;
      RECT 1.960 2.100 2.240 130.900 ;
      RECT 5.320 2.100 5.600 130.900 ;
      RECT 8.680 2.100 8.960 130.900 ;
      RECT 12.040 2.100 12.320 130.900 ;
      RECT 15.400 2.100 15.680 130.900 ;
      RECT 18.760 2.100 19.040 130.900 ;
      RECT 22.120 2.100 22.400 130.900 ;
      RECT 25.480 2.100 25.760 130.900 ;
      RECT 28.840 2.100 29.120 130.900 ;
      RECT 32.200 2.100 32.480 130.900 ;
      RECT 35.560 2.100 35.840 130.900 ;
      RECT 38.920 2.100 39.200 130.900 ;
      RECT 42.280 2.100 42.560 130.900 ;
      RECT 45.640 2.100 45.920 130.900 ;
      RECT 49.000 2.100 49.280 130.900 ;
      RECT 52.360 2.100 52.640 130.900 ;
      RECT 55.720 2.100 56.000 130.900 ;
      RECT 59.080 2.100 59.360 130.900 ;
      RECT 62.440 2.100 62.720 130.900 ;
      RECT 65.800 2.100 66.080 130.900 ;
      RECT 69.160 2.100 69.440 130.900 ;
      RECT 72.520 2.100 72.800 130.900 ;
      RECT 75.880 2.100 76.160 130.900 ;
      RECT 79.240 2.100 79.520 130.900 ;
      RECT 82.600 2.100 82.880 130.900 ;
      RECT 85.960 2.100 86.240 130.900 ;
      RECT 89.320 2.100 89.600 130.900 ;
      RECT 92.680 2.100 92.960 130.900 ;
      RECT 96.040 2.100 96.320 130.900 ;
      RECT 99.400 2.100 99.680 130.900 ;
      RECT 102.760 2.100 103.040 130.900 ;
      RECT 106.120 2.100 106.400 130.900 ;
      RECT 109.480 2.100 109.760 130.900 ;
      RECT 112.840 2.100 113.120 130.900 ;
      RECT 116.200 2.100 116.480 130.900 ;
      RECT 119.560 2.100 119.840 130.900 ;
      RECT 122.920 2.100 123.200 130.900 ;
      RECT 126.280 2.100 126.560 130.900 ;
    END
  END VSS
  PIN VDD
    DIRECTION INOUT ;
    USE POWER ;
    PORT
      LAYER metal4 ;
      RECT 3.640 2.100 3.920 130.900 ;
      RECT 7.000 2.100 7.280 130.900 ;
      RECT 10.360 2.100 10.640 130.900 ;
      RECT 13.720 2.100 14.000 130.900 ;
      RECT 17.080 2.100 17.360 130.900 ;
      RECT 20.440 2.100 20.720 130.900 ;
      RECT 23.800 2.100 24.080 130.900 ;
      RECT 27.160 2.100 27.440 130.900 ;
      RECT 30.520 2.100 30.800 130.900 ;
      RECT 33.880 2.100 34.160 130.900 ;
      RECT 37.240 2.100 37.520 130.900 ;
      RECT 40.600 2.100 40.880 130.900 ;
      RECT 43.960 2.100 44.240 130.900 ;
      RECT 47.320 2.100 47.600 130.900 ;
      RECT 50.680 2.100 50.960 130.900 ;
      RECT 54.040 2.100 54.320 130.900 ;
      RECT 57.400 2.100 57.680 130.900 ;
      RECT 60.760 2.100 61.040 130.900 ;
      RECT 64.120 2.100 64.400 130.900 ;
      RECT 67.480 2.100 67.760 130.900 ;
      RECT 70.840 2.100 71.120 130.900 ;
      RECT 74.200 2.100 74.480 130.900 ;
      RECT 77.560 2.100 77.840 130.900 ;
      RECT 80.920 2.100 81.200 130.900 ;
      RECT 84.280 2.100 84.560 130.900 ;
      RECT 87.640 2.100 87.920 130.900 ;
      RECT 91.000 2.100 91.280 130.900 ;
      RECT 94.360 2.100 94.640 130.900 ;
      RECT 97.720 2.100 98.000 130.900 ;
      RECT 101.080 2.100 101.360 130.900 ;
      RECT 104.440 2.100 104.720 130.900 ;
      RECT 107.800 2.100 108.080 130.900 ;
      RECT 111.160 2.100 111.440 130.900 ;
      RECT 114.520 2.100 114.800 130.900 ;
      RECT 117.880 2.100 118.160 130.900 ;
      RECT 121.240 2.100 121.520 130.900 ;
      RECT 124.600 2.100 124.880 130.900 ;
      RECT 127.960 2.100 128.240 130.900 ;
    END
  END VDD
  OBS
    LAYER metal1 ;
    RECT 0 0 132.620 133.000 ;
    LAYER metal2 ;
    RECT 0 0 132.620 133.000 ;
    LAYER metal3 ;
    RECT 0.070 0 132.620 133.000 ;
    RECT 0 0.000 0.070 2.070 ;
    RECT 0 2.270 0.070 2.350 ;
    RECT 0 2.550 0.070 2.630 ;
    RECT 0 2.830 0.070 2.910 ;
    RECT 0 3.110 0.070 3.190 ;
    RECT 0 3.390 0.070 3.470 ;
    RECT 0 3.670 0.070 3.750 ;
    RECT 0 3.950 0.070 4.030 ;
    RECT 0 4.230 0.070 4.310 ;
    RECT 0 4.510 0.070 4.590 ;
    RECT 0 4.790 0.070 4.870 ;
    RECT 0 5.070 0.070 5.150 ;
    RECT 0 5.350 0.070 5.430 ;
    RECT 0 5.630 0.070 5.710 ;
    RECT 0 5.910 0.070 5.990 ;
    RECT 0 6.190 0.070 6.270 ;
    RECT 0 6.470 0.070 6.550 ;
    RECT 0 6.750 0.070 6.830 ;
    RECT 0 7.030 0.070 7.110 ;
    RECT 0 7.310 0.070 7.390 ;
    RECT 0 7.590 0.070 7.670 ;
    RECT 0 7.870 0.070 7.950 ;
    RECT 0 8.150 0.070 8.230 ;
    RECT 0 8.430 0.070 8.510 ;
    RECT 0 8.710 0.070 8.790 ;
    RECT 0 8.990 0.070 9.070 ;
    RECT 0 9.270 0.070 9.350 ;
    RECT 0 9.550 0.070 9.630 ;
    RECT 0 9.830 0.070 9.910 ;
    RECT 0 10.110 0.070 10.190 ;
    RECT 0 10.390 0.070 10.470 ;
    RECT 0 10.670 0.070 10.750 ;
    RECT 0 10.950 0.070 11.030 ;
    RECT 0 11.230 0.070 11.310 ;
    RECT 0 11.510 0.070 11.590 ;
    RECT 0 11.790 0.070 11.870 ;
    RECT 0 12.070 0.070 12.150 ;
    RECT 0 12.350 0.070 12.430 ;
    RECT 0 12.630 0.070 12.710 ;
    RECT 0 12.910 0.070 12.990 ;
    RECT 0 13.190 0.070 13.270 ;
    RECT 0 13.470 0.070 13.550 ;
    RECT 0 13.750 0.070 13.830 ;
    RECT 0 14.030 0.070 14.110 ;
    RECT 0 14.310 0.070 14.390 ;
    RECT 0 14.590 0.070 14.670 ;
    RECT 0 14.870 0.070 14.950 ;
    RECT 0 15.150 0.070 15.230 ;
    RECT 0 15.430 0.070 15.510 ;
    RECT 0 15.710 0.070 15.790 ;
    RECT 0 15.990 0.070 16.070 ;
    RECT 0 16.270 0.070 16.350 ;
    RECT 0 16.550 0.070 16.630 ;
    RECT 0 16.830 0.070 16.910 ;
    RECT 0 17.110 0.070 17.190 ;
    RECT 0 17.390 0.070 17.470 ;
    RECT 0 17.670 0.070 17.750 ;
    RECT 0 17.950 0.070 18.030 ;
    RECT 0 18.230 0.070 18.310 ;
    RECT 0 18.510 0.070 19.430 ;
    RECT 0 19.630 0.070 19.710 ;
    RECT 0 19.910 0.070 19.990 ;
    RECT 0 20.190 0.070 20.270 ;
    RECT 0 20.470 0.070 20.550 ;
    RECT 0 20.750 0.070 20.830 ;
    RECT 0 21.030 0.070 21.110 ;
    RECT 0 21.310 0.070 21.390 ;
    RECT 0 21.590 0.070 21.670 ;
    RECT 0 21.870 0.070 21.950 ;
    RECT 0 22.150 0.070 22.230 ;
    RECT 0 22.430 0.070 22.510 ;
    RECT 0 22.710 0.070 22.790 ;
    RECT 0 22.990 0.070 23.070 ;
    RECT 0 23.270 0.070 23.350 ;
    RECT 0 23.550 0.070 23.630 ;
    RECT 0 23.830 0.070 23.910 ;
    RECT 0 24.110 0.070 24.190 ;
    RECT 0 24.390 0.070 24.470 ;
    RECT 0 24.670 0.070 24.750 ;
    RECT 0 24.950 0.070 25.030 ;
    RECT 0 25.230 0.070 25.310 ;
    RECT 0 25.510 0.070 25.590 ;
    RECT 0 25.790 0.070 25.870 ;
    RECT 0 26.070 0.070 26.150 ;
    RECT 0 26.350 0.070 26.430 ;
    RECT 0 26.630 0.070 26.710 ;
    RECT 0 26.910 0.070 26.990 ;
    RECT 0 27.190 0.070 27.270 ;
    RECT 0 27.470 0.070 27.550 ;
    RECT 0 27.750 0.070 27.830 ;
    RECT 0 28.030 0.070 28.110 ;
    RECT 0 28.310 0.070 28.390 ;
    RECT 0 28.590 0.070 28.670 ;
    RECT 0 28.870 0.070 28.950 ;
    RECT 0 29.150 0.070 29.230 ;
    RECT 0 29.430 0.070 29.510 ;
    RECT 0 29.710 0.070 29.790 ;
    RECT 0 29.990 0.070 30.070 ;
    RECT 0 30.270 0.070 30.350 ;
    RECT 0 30.550 0.070 30.630 ;
    RECT 0 30.830 0.070 30.910 ;
    RECT 0 31.110 0.070 31.190 ;
    RECT 0 31.390 0.070 31.470 ;
    RECT 0 31.670 0.070 31.750 ;
    RECT 0 31.950 0.070 32.030 ;
    RECT 0 32.230 0.070 32.310 ;
    RECT 0 32.510 0.070 32.590 ;
    RECT 0 32.790 0.070 32.870 ;
    RECT 0 33.070 0.070 33.150 ;
    RECT 0 33.350 0.070 33.430 ;
    RECT 0 33.630 0.070 33.710 ;
    RECT 0 33.910 0.070 33.990 ;
    RECT 0 34.190 0.070 34.270 ;
    RECT 0 34.470 0.070 34.550 ;
    RECT 0 34.750 0.070 34.830 ;
    RECT 0 35.030 0.070 35.110 ;
    RECT 0 35.310 0.070 35.390 ;
    RECT 0 35.590 0.070 35.670 ;
    RECT 0 35.870 0.070 36.790 ;
    RECT 0 36.990 0.070 37.070 ;
    RECT 0 37.270 0.070 37.350 ;
    RECT 0 37.550 0.070 37.630 ;
    RECT 0 37.830 0.070 37.910 ;
    RECT 0 38.110 0.070 38.190 ;
    RECT 0 38.390 0.070 38.470 ;
    RECT 0 38.670 0.070 38.750 ;
    RECT 0 38.950 0.070 39.030 ;
    RECT 0 39.230 0.070 39.310 ;
    RECT 0 39.510 0.070 39.590 ;
    RECT 0 39.790 0.070 39.870 ;
    RECT 0 40.070 0.070 40.150 ;
    RECT 0 40.350 0.070 40.430 ;
    RECT 0 40.630 0.070 40.710 ;
    RECT 0 40.910 0.070 40.990 ;
    RECT 0 41.190 0.070 41.270 ;
    RECT 0 41.470 0.070 41.550 ;
    RECT 0 41.750 0.070 41.830 ;
    RECT 0 42.030 0.070 42.110 ;
    RECT 0 42.310 0.070 42.390 ;
    RECT 0 42.590 0.070 42.670 ;
    RECT 0 42.870 0.070 42.950 ;
    RECT 0 43.150 0.070 43.230 ;
    RECT 0 43.430 0.070 43.510 ;
    RECT 0 43.710 0.070 43.790 ;
    RECT 0 43.990 0.070 44.070 ;
    RECT 0 44.270 0.070 44.350 ;
    RECT 0 44.550 0.070 44.630 ;
    RECT 0 44.830 0.070 44.910 ;
    RECT 0 45.110 0.070 45.190 ;
    RECT 0 45.390 0.070 45.470 ;
    RECT 0 45.670 0.070 45.750 ;
    RECT 0 45.950 0.070 46.030 ;
    RECT 0 46.230 0.070 46.310 ;
    RECT 0 46.510 0.070 46.590 ;
    RECT 0 46.790 0.070 46.870 ;
    RECT 0 47.070 0.070 47.150 ;
    RECT 0 47.350 0.070 47.430 ;
    RECT 0 47.630 0.070 47.710 ;
    RECT 0 47.910 0.070 47.990 ;
    RECT 0 48.190 0.070 48.270 ;
    RECT 0 48.470 0.070 48.550 ;
    RECT 0 48.750 0.070 48.830 ;
    RECT 0 49.030 0.070 49.110 ;
    RECT 0 49.310 0.070 49.390 ;
    RECT 0 49.590 0.070 49.670 ;
    RECT 0 49.870 0.070 49.950 ;
    RECT 0 50.150 0.070 50.230 ;
    RECT 0 50.430 0.070 50.510 ;
    RECT 0 50.710 0.070 50.790 ;
    RECT 0 50.990 0.070 51.070 ;
    RECT 0 51.270 0.070 51.350 ;
    RECT 0 51.550 0.070 51.630 ;
    RECT 0 51.830 0.070 51.910 ;
    RECT 0 52.110 0.070 52.190 ;
    RECT 0 52.390 0.070 52.470 ;
    RECT 0 52.670 0.070 52.750 ;
    RECT 0 52.950 0.070 53.030 ;
    RECT 0 53.230 0.070 54.150 ;
    RECT 0 54.350 0.070 54.430 ;
    RECT 0 54.630 0.070 54.710 ;
    RECT 0 54.910 0.070 54.990 ;
    RECT 0 55.190 0.070 55.270 ;
    RECT 0 55.470 0.070 55.550 ;
    RECT 0 55.750 0.070 55.830 ;
    RECT 0 56.030 0.070 56.110 ;
    RECT 0 56.310 0.070 56.390 ;
    RECT 0 56.590 0.070 56.670 ;
    RECT 0 56.870 0.070 56.950 ;
    RECT 0 57.150 0.070 57.230 ;
    RECT 0 57.430 0.070 133.000 ;
    LAYER metal4 ;
    RECT 0 0 132.620 2.100 ;
    RECT 0 130.900 132.620 133.000 ;
    RECT 0.000 2.100 1.960 130.900 ;
    RECT 2.240 2.100 3.640 130.900 ;
    RECT 3.920 2.100 5.320 130.900 ;
    RECT 5.600 2.100 7.000 130.900 ;
    RECT 7.280 2.100 8.680 130.900 ;
    RECT 8.960 2.100 10.360 130.900 ;
    RECT 10.640 2.100 12.040 130.900 ;
    RECT 12.320 2.100 13.720 130.900 ;
    RECT 14.000 2.100 15.400 130.900 ;
    RECT 15.680 2.100 17.080 130.900 ;
    RECT 17.360 2.100 18.760 130.900 ;
    RECT 19.040 2.100 20.440 130.900 ;
    RECT 20.720 2.100 22.120 130.900 ;
    RECT 22.400 2.100 23.800 130.900 ;
    RECT 24.080 2.100 25.480 130.900 ;
    RECT 25.760 2.100 27.160 130.900 ;
    RECT 27.440 2.100 28.840 130.900 ;
    RECT 29.120 2.100 30.520 130.900 ;
    RECT 30.800 2.100 32.200 130.900 ;
    RECT 32.480 2.100 33.880 130.900 ;
    RECT 34.160 2.100 35.560 130.900 ;
    RECT 35.840 2.100 37.240 130.900 ;
    RECT 37.520 2.100 38.920 130.900 ;
    RECT 39.200 2.100 40.600 130.900 ;
    RECT 40.880 2.100 42.280 130.900 ;
    RECT 42.560 2.100 43.960 130.900 ;
    RECT 44.240 2.100 45.640 130.900 ;
    RECT 45.920 2.100 47.320 130.900 ;
    RECT 47.600 2.100 49.000 130.900 ;
    RECT 49.280 2.100 50.680 130.900 ;
    RECT 50.960 2.100 52.360 130.900 ;
    RECT 52.640 2.100 54.040 130.900 ;
    RECT 54.320 2.100 55.720 130.900 ;
    RECT 56.000 2.100 57.400 130.900 ;
    RECT 57.680 2.100 59.080 130.900 ;
    RECT 59.360 2.100 60.760 130.900 ;
    RECT 61.040 2.100 62.440 130.900 ;
    RECT 62.720 2.100 64.120 130.900 ;
    RECT 64.400 2.100 65.800 130.900 ;
    RECT 66.080 2.100 67.480 130.900 ;
    RECT 67.760 2.100 69.160 130.900 ;
    RECT 69.440 2.100 70.840 130.900 ;
    RECT 71.120 2.100 72.520 130.900 ;
    RECT 72.800 2.100 74.200 130.900 ;
    RECT 74.480 2.100 75.880 130.900 ;
    RECT 76.160 2.100 77.560 130.900 ;
    RECT 77.840 2.100 79.240 130.900 ;
    RECT 79.520 2.100 80.920 130.900 ;
    RECT 81.200 2.100 82.600 130.900 ;
    RECT 82.880 2.100 84.280 130.900 ;
    RECT 84.560 2.100 85.960 130.900 ;
    RECT 86.240 2.100 87.640 130.900 ;
    RECT 87.920 2.100 89.320 130.900 ;
    RECT 89.600 2.100 91.000 130.900 ;
    RECT 91.280 2.100 92.680 130.900 ;
    RECT 92.960 2.100 94.360 130.900 ;
    RECT 94.640 2.100 96.040 130.900 ;
    RECT 96.320 2.100 97.720 130.900 ;
    RECT 98.000 2.100 99.400 130.900 ;
    RECT 99.680 2.100 101.080 130.900 ;
    RECT 101.360 2.100 102.760 130.900 ;
    RECT 103.040 2.100 104.440 130.900 ;
    RECT 104.720 2.100 106.120 130.900 ;
    RECT 106.400 2.100 107.800 130.900 ;
    RECT 108.080 2.100 109.480 130.900 ;
    RECT 109.760 2.100 111.160 130.900 ;
    RECT 111.440 2.100 112.840 130.900 ;
    RECT 113.120 2.100 114.520 130.900 ;
    RECT 114.800 2.100 116.200 130.900 ;
    RECT 116.480 2.100 117.880 130.900 ;
    RECT 118.160 2.100 119.560 130.900 ;
    RECT 119.840 2.100 121.240 130.900 ;
    RECT 121.520 2.100 122.920 130.900 ;
    RECT 123.200 2.100 124.600 130.900 ;
    RECT 124.880 2.100 126.280 130.900 ;
    RECT 126.560 2.100 127.960 130.900 ;
    RECT 128.240 2.100 132.620 130.900 ;
    LAYER OVERLAP ;
    RECT 0 0 132.620 133.000 ;
  END
END fakeram45_512x59

END LIBRARY
